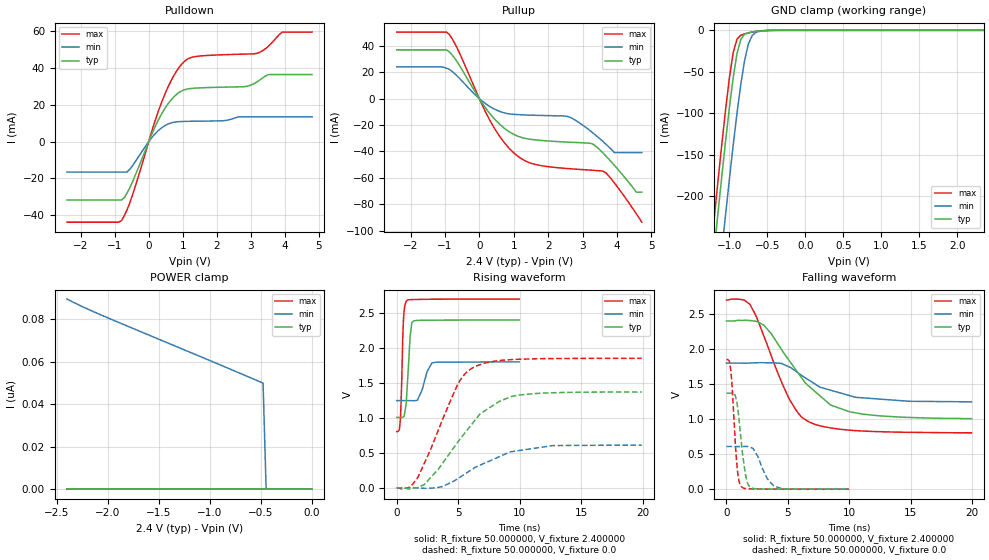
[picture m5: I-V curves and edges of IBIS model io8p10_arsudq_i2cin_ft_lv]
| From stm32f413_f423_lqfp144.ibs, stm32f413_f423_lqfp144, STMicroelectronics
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|   Model io8p10_arsudq_i2cin_ft_lv
[Model]  io8p10_arsudq_i2cin_ft_lv
Model_type I/O
Polarity   Non-Inverting
Enable   Active-Low
Vinl =   0.720000V
Vinh =   1.680000V
Vmeas =  1.200000V
Cref =   40.000000pF
Rref =   100.000000M
Vref =   0.0V
C_comp   2.230300pF   2.174000pF   2.332300pF
[Temperature Range]   25.000000   0.125000k   -40.000000
[Pullup Reference]   2.400000V   1.800000V   2.700000V
[Pulldown Reference]   0.0V   0.0V   0.0V
[POWER Clamp Reference]   2.400000V   1.800000V   2.700000V
[GND Clamp Reference]   0.0V   0.0V   0.0V
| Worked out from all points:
|   slope of the pulldown table from 0 to 0.36 V, typ, clamps not added: 25 ohm
|   slope of the pullup table from 0 to 0.36 V, typ, clamps not added: 27.7 ohm
|   GND clamp passes 1 mA (typ) near -0.62 V on its own axis
|   rising waveform, R_fixture 50.000000, V_fixture 2.400000: 20-80 % time 278ps typ, 606ps min, 184ps max; typ from 1.01 V to 2.4 V
|   rising waveform, R_fixture 50.000000, V_fixture 0.0: 20-80 % time 3.71ns typ, 4.01ns min, 2.67ns max; typ from 0 V to 1.37 V
|   falling waveform, R_fixture 50.000000, V_fixture 2.400000: 20-80 % time 3.91ns typ, 3.98ns min, 2.72ns max; typ from 2.4 V to 1.01 V
|   falling waveform, R_fixture 50.000000, V_fixture 0.0: 20-80 % time 530ps typ, 976ps min, 385ps max; typ from 1.37 V to 0 V
[Pulldown]
|Voltage   I(typ)   I(min)   I(max)
-2.4V     -31.73mA   -16.51mA   -43.74mA
-800mV    -31.73mA   -16.51mA   -42.87mA
-480mV    -21.98mA   -13.17mA   -29.21mA
80mV      3.63mA     1.966mA    5.014mA
480mV     18.16mA    8.738mA    26.02mA
800mV     25.38mA    10.72mA    37.77mA
1.12V     28.53mA    11.02mA    44.6mA
2.8V      29.84mA    13.49mA    47.53mA
3.2V      32.65mA    13.49mA    48.05mA
3.52V     36.43mA    13.49mA    51.84mA
3.92V     36.43mA    13.49mA    59.49mA
4.8V      36.43mA    13.49mA    59.49mA
[Pullup]
|Voltage   I(typ)   I(min)   I(max)
-2.4V     36.91mA    24.04mA    50.37mA
-960mV    36.91mA    23.05mA    50.37mA
-640mV    27.65mA    17.03mA    38mA
320mV     -11.75mA   -6.207mA   -17.08mA
960mV     -26.47mA   -11.82mA   -40.02mA
1.52V     -30.88mA   -12.51mA   -49.05mA
2.56V     -32.88mA   -13.48mA   -52.9mA
3.28V     -34.19mA   -25.52mA   -54.18mA
3.6V      -41.31mA   -32.62mA   -54.97mA
3.92V     -50.33mA   -40.8mA    -63.62mA
4.56V     -70.8mA    -40.8mA    -87.07mA
4.72V     -70.8mA    -40.8mA    -93.5mA
[GND_clamp]
|Voltage   I(typ)   I(min)   I(max)
-2.4V     -1.424A    -1.508A    -1.393A
-1.25V    -311.2mA   -401.9mA   -273.3mA
-1.2V     -265.4mA   -356.1mA   -227.2mA
-1.15V    -220.4mA   -310.8mA   -181.9mA
-1.1V     -176.3mA   -266.2mA   -137.9mA
-1.05V    -133.8mA   -222.5mA   -95.87mA
-950mV    -57.3mA    -138.9mA   -26.98mA
-900mV    -28.27mA   -100.4mA   -10.59mA
-850mV    -11.01mA   -65.54mA   -5.958mA
-750mV    -2.834mA   -16.5mA    -3.178mA
-600mV    -750uA     -1.164mA   -738.3uA
2.35V     0A         0A         0A
[POWER_clamp]
|Voltage   I(typ)   I(min)   I(max)
-2.4V     0A         89.62nA    0A
-2.04V    0A         81.57nA    0A
-480mV    0A         50.01nA    0A
-450mV    0A         0A         0A
0V        0A         0A         0A
[Ramp]
| variable   typ   min   max
dV/dt_r  0.82194/3.70293n   0.36595/4.01611n   1.11114/2.67085n
dV/dt_f  0.83268/3.90930n   0.33246/4.03252n   1.13625/2.72185n
R_load = 50.000000
[Rising Waveform]
R_fixture= 50.000000
V_fixture= 2.400000
V_fixture_min= 1.800000
V_fixture_max= 2.700000
|time   V(typ)   V(min)   V(max)
0s        1.006V     1.247V     804.6mV
200.2ps   1.006V     1.247V     825.6mV
300.3ps   1.006V     1.247V     989.2mV
560.6ps   1.015V     1.247V     2.441V
820.8ps   1.355V     1.247V     2.675V
1.101ns   2.182V     1.247V     2.691V
1.341ns   2.381V     1.245V     2.692V
1.682ns   2.394V     1.253V     2.694V
2.883ns   2.397V     1.787V     2.697V
9.97ns    2.4V       1.8V       2.699V
[Rising Waveform]
R_fixture= 50.000000
V_fixture= 0.0
V_fixture_min= 0.0
V_fixture_max= 0.0
|time   V(typ)   V(min)   V(max)
0s        169uV      66.49uV    559.6uV
1.121ns   -14.43mV   129.7uV    14.51mV
1.722ns   5.596mV    -1.064mV   149.4mV
3.323ns   253.4mV    4.113mV    799.3mV
4.925ns   642.5mV    126.4mV    1.465V
6.246ns   939.4mV    277.1mV    1.722V
6.807ns   1.06V      325.6mV    1.762V
9.369ns   1.308V     517.2mV    1.834V
12.73ns   1.359V     603.8mV    1.848V
19.94ns   1.37V      609mV      1.852V
[Falling Waveform]
R_fixture= 50.000000
V_fixture= 2.400000
V_fixture_min= 1.800000
V_fixture_max= 2.700000
|time   V(typ)   V(min)   V(max)
0s        2.4V       1.8V       2.699V
1.441ns   2.41V      1.8V       2.699V
1.922ns   2.407V     1.801V     2.635V
3.043ns   2.341V     1.805V     2.187V
5.085ns   1.841V     1.746V     1.294V
6.046ns   1.606V     1.633V     1.041V
6.767ns   1.461V     1.55V      956mV
8.488ns   1.2V       1.412V     874mV
10.05ns   1.103V     1.334V     841.7mV
19.94ns   1.006V     1.247V     804.6mV
[Falling Waveform]
R_fixture= 50.000000
V_fixture= 0.0
V_fixture_min= 0.0
V_fixture_max= 0.0
|time   V(typ)   V(min)   V(max)
0s        1.37V      609mV      1.852V
340.3ps   1.37V      609mV      1.719V
440.4ps   1.37V      609mV      1.521V
700.7ps   1.343V     608.9mV    720.9mV
940.9ps   1.122V     608.7mV    199.3mV
1.221ns   652.3mV    608.5mV    36.23mV
1.682ns   103.7mV    610.1mV    5.934mV
2.042ns   17.64mV    590.6mV    3.774mV
3.844ns   1.556mV    47.2mV     1.44mV
9.97ns    169uV      66.49uV    559.6uV
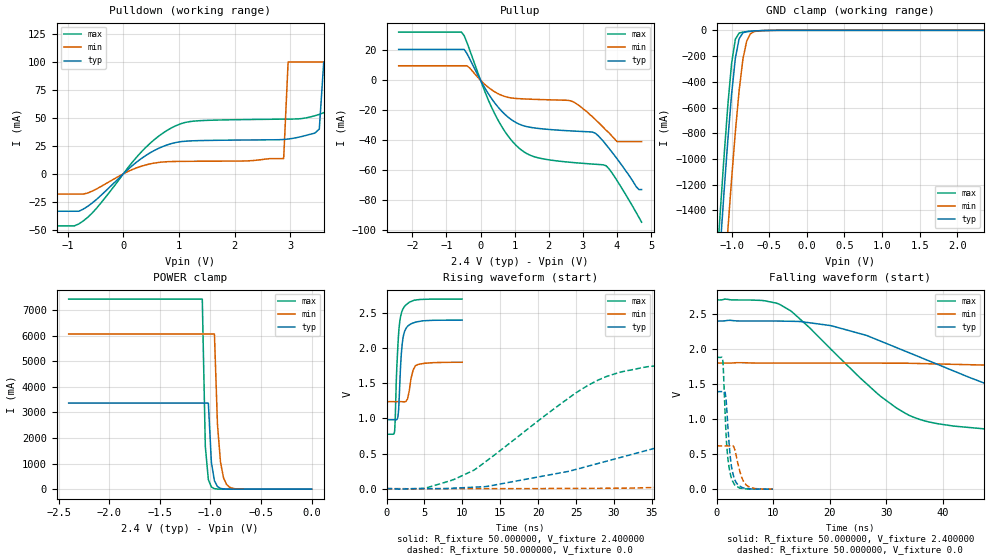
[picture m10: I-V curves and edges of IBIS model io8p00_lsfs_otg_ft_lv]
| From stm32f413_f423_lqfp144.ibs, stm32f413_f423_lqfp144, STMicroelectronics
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|   Model io8p00_lsfs_otg_ft_lv
[Model]  io8p00_lsfs_otg_ft_lv
Model_type I/O
Polarity   Non-Inverting
Enable   Active-Low
Vinl =   0.720000V
Vinh =   1.680000V
Vmeas =  1.200000V
Cref =   50.000000pF
Rref =   100.000000M
Vref =   0.0V
C_comp   7.971100pF   7.737700pF   8.264100pF
[Temperature Range]   25.000000   0.125000k   -40.000000
[Pullup Reference]   2.400000V   1.800000V   2.700000V
[Pulldown Reference]   0.0V   0.0V   0.0V
[POWER Clamp Reference]   2.400000V   1.800000V   2.700000V
[GND Clamp Reference]   0.0V   0.0V   0.0V
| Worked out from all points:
|   slope of the pulldown table from 0 to 0.36 V, typ, clamps not added: 24.1 ohm
|   slope of the pullup table from 0 to 0.36 V, typ, clamps not added: 26.8 ohm
|   GND clamp passes 1 mA (typ) near -0.52 V on its own axis
|   POWER clamp passes 1 mA (typ) near -0.81 V on its own axis
|   rising waveform, R_fixture 50.000000, V_fixture 2.400000: 20-80 % time 477ps typ, 592ps min, 489ps max; typ from 0.981 V to 2.4 V
|   rising waveform, R_fixture 50.000000, V_fixture 0.0: 20-80 % time 30.9ns typ, 82ns min, 14.2ns max; typ from 0 V to 1.39 V
|   falling waveform, R_fixture 50.000000, V_fixture 2.400000: 20-80 % time 28.5ns typ, 70.3ns min, 15.5ns max; typ from 2.4 V to 0.981 V
|   falling waveform, R_fixture 50.000000, V_fixture 0.0: 20-80 % time 913ps typ, 1.27ns min, 797ps max; typ from 1.39 V to 0 V
[Pulldown]
|Voltage   I(typ)   I(min)   I(max)
-2.4V     -33.44mA   -18.12mA   -46.52mA
-800mV    -33.44mA   -18.12mA   -44.78mA
1.04V     28.81mA    11.14mA    44.91mA
2.88V     30.71mA    13.65mA    48.89mA
2.96V     31.11mA    100mA      48.94mA
3.52V     40mA       100mA      53.15mA
3.6V      100mA      100mA      54.66mA
3.92V     100mA      100mA      60mA
4V        100mA      100mA      100mA
4.4V      100mA      100mA      100mA
4.48V     100mA      100mA      1A
4.8V      100mA      100mA      1A
[Pullup]
|Voltage   I(typ)   I(min)   I(max)
-2.4V     20.56mA    9.686mA    32.17mA
-560mV    20.56mA    9.686mA    32.17mA
-400mV    17.87mA    9.686mA    25.31mA
320mV     -12.14mA   -6.322mA   -17.91mA
960mV     -27.18mA   -12mA      -41.54mA
1.52V     -31.65mA   -12.71mA   -50.67mA
2.64V     -33.82mA   -13.73mA   -54.81mA
3.36V     -35.34mA   -26.1mA    -56.1mA
3.68V     -43.1mA    -33.4mA    -57.12mA
4V        -52.4mA    -41mA      -67mA
4.56V     -71mA      -41mA      -88.3mA
4.72V     -73mA      -41mA      -94.8mA
[GND_clamp]
|Voltage   I(typ)   I(min)   I(max)
-2.4V     -9.766A    -9.942A    -9.572A
-1.2V     -2.124A    -2.851A    -1.855A
-1.15V    -1.682A    -2.408A    -1.408A
-1.1V     -1.256A    -1.975A    -979.8mA
-1.05V    -854.9mA   -1.556A    -584.5mA
-1V       -496.5mA   -1.158A    -257.5mA
-950mV    -217.7mA   -789.6mA   -69.52mA
-900mV    -65.57mA   -469.8mA   -21.5mA
-850mV    -19.64mA   -226.4mA   -13.56mA
-800mV    -9.753mA   -84.21mA   -10.47mA
-700mV    -4.923mA   -9.884mA   -5.807mA
2.35V     0A         0A         0A
[POWER_clamp]
|Voltage   I(typ)   I(min)   I(max)
-2.4V     3.365A     6.064A     7.43A
-1.08V    3.365A     6.064A     7.43A
-1.05V    3.365A     6.064A     1.669A
-1.02V    3.365A     6.064A     375mA
-990mV    1.047A     6.064A     84.24mA
-960mV    325.6mA    6.064A     18.93mA
-930mV    101.3mA    2.529A     4.252mA
-900mV    31.51mA    1.055A     955.2uA
-870mV    9.804mA    440.1mA    214.6uA
-840mV    3.05mA     183.6mA    74uA
-720mV    28.58uA    5.557mA    74uA
0V        0A         0A         0A
[Ramp]
| variable   typ   min   max
dV/dt_r  0.83538/30.87827n   0.36567/82.44543n   1.12860/14.17351n
dV/dt_f  0.85169/28.51039n   0.33204/72.06161n   1.15501/15.47388n
R_load = 50.000000
[Rising Waveform]
R_fixture= 50.000000
V_fixture= 2.400000
V_fixture_min= 1.800000
V_fixture_max= 2.700000
|time   V(typ)   V(min)   V(max)
0s        981.3mV    1.239V     774.8mV
1.061ns   981.2mV    1.239V     815mV
1.141ns   980.9mV    1.239V     974.8mV
1.341ns   983.2mV    1.239V     1.687V
1.562ns   1.086V     1.239V     2.156V
1.942ns   1.905V     1.239V     2.492V
2.182ns   2.151V     1.237V     2.562V
2.783ns   2.312V     1.282V     2.636V
3.824ns   2.371V     1.752V     2.686V
9.97ns    2.4V       1.8V       2.7V
[Rising Waveform]
R_fixture= 50.000000
V_fixture= 0.0
V_fixture_min= 0.0
V_fixture_max= 0.0
|time   V(typ)   V(min)   V(max)
0s        3.299uV    1.724uV    7.414uV
5.005ns   -281.7uV   -688.8uV   4.285mV
11.51ns   20.85mV    -38.54uV   262.6mV
24.52ns   260.9mV    3.536mV    1.33V
29.03ns   391.5mV    5.86mV     1.598V
41.54ns   760.4mV    36.52mV    1.812V
62.06ns   1.213V     102.2mV    1.868V
78.58ns   1.331V     184.9mV    1.88V
165.7ns   1.391V     548.3mV    1.881V
249.2ns   1.392V     617.9mV    1.881V
[Falling Waveform]
R_fixture= 50.000000
V_fixture= 2.400000
V_fixture_min= 1.800000
V_fixture_max= 2.700000
|time   V(typ)   V(min)   V(max)
0s        2.4V       1.8V       2.7V
11.01ns   2.399V     1.8V       2.644V
20.52ns   2.328V     1.8V       1.974V
31.53ns   2.03V      1.798V     1.175V
36.04ns   1.881V     1.793V     992.8mV
42.04ns   1.683V     1.781V     899.4mV
60.06ns   1.224V     1.72V      814.5mV
85.09ns   1.056V     1.571V     786mV
158.7ns   989.4mV    1.293V     775.2mV
249.2ns   981.3mV    1.239V     774.8mV
[Falling Waveform]
R_fixture= 50.000000
V_fixture= 0.0
V_fixture_min= 0.0
V_fixture_max= 0.0
|time   V(typ)   V(min)   V(max)
0s        1.392V     617.9mV    1.881V
1.081ns   1.393V     617.9mV    1.851V
1.522ns   1.379V     617.9mV    1.076V
1.842ns   1.1V       617.5mV    585.3mV
2.402ns   480.6mV    619.1mV    231.5mV
2.763ns   271.1mV    622.1mV    126.6mV
3.524ns   88.8mV     460.8mV    44.48mV
4.484ns   26.15mV    161.5mV    10.8mV
5.285ns   11.8mV     55.96mV    3.012mV
9.97ns    3.299uV    1.724uV    7.414uV
